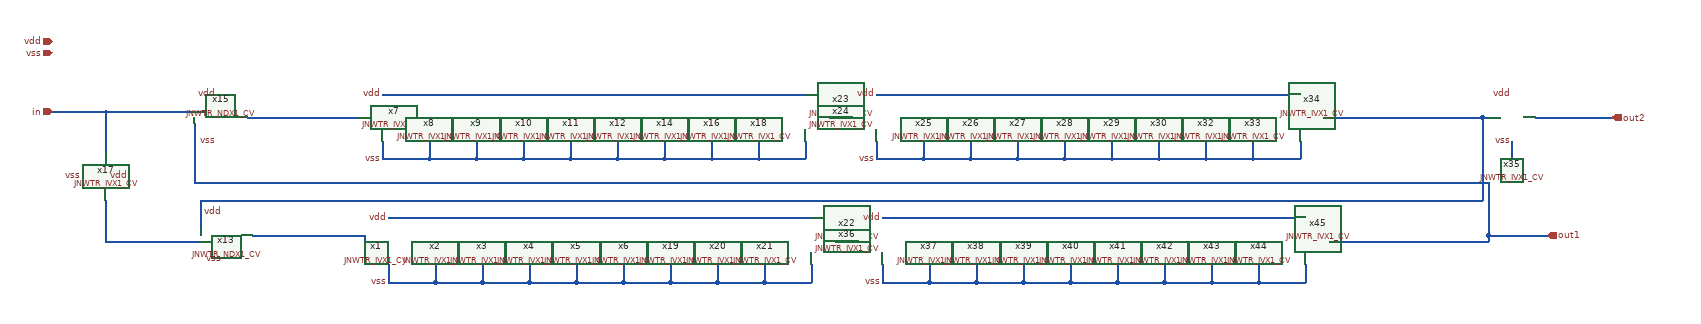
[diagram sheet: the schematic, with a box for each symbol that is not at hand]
v {xschem version=3.4.5 file_version=1.2
}
G {}
K {}
V {}
S {}
E {}
N 170 -220 170 -150 {
lab=#net1}
N 170 -150 330 -150 {
lab=#net1}
N 170 -370 320 -370 {
lab=in}
N 170 -370 170 -300 {
lab=in}
N 80 -370 170 -370 {
lab=in}
N 320 -250 2520 -250 {
lab=out1}
N 320 -350 320 -250 {
lab=out1}
N 330 -220 330 -170 {
lab=#net2}
N 2560 -320 2560 -290 {
lab=vss}
N 2520 -250 2520 -160 {
lab=out1}
N 640 -320 640 -290 {
lab=vss}
N 720 -320 720 -290 {
lab=vss}
N 800 -320 800 -290 {
lab=vss}
N 880 -320 880 -290 {
lab=vss}
N 960 -320 960 -290 {
lab=vss}
N 1040 -320 1040 -290 {
lab=vss}
N 960 -290 1040 -290 {
lab=vss}
N 640 -290 720 -290 {
lab=vss}
N 720 -290 800 -290 {
lab=vss}
N 800 -290 880 -290 {
lab=vss}
N 880 -290 960 -290 {
lab=vss}
N 2510 -360 2510 -220 {
lab=#net2}
N 2520 -160 2620 -160 {
lab=out1}
N 2600 -360 2730 -360 {
lab=out2}
N 1120 -320 1120 -290 {
lab=vss}
N 1200 -320 1200 -290 {
lab=vss}
N 1200 -290 1280 -290 {
lab=vss}
N 1040 -290 1120 -290 {
lab=vss}
N 1120 -290 1200 -290 {
lab=vss}
N 640 -400 1360 -400 {
lab=vdd}
N 1280 -290 1360 -290 {
lab=vss}
N 1280 -320 1280 -290 {
lab=vss}
N 1360 -320 1360 -290 {
lab=vss}
N 2510 -360 2520 -360 {
lab=#net2}
N 330 -220 2510 -220 {
lab=#net2}
N 650 -110 650 -80 {
lab=vss}
N 730 -110 730 -80 {
lab=vss}
N 810 -110 810 -80 {
lab=vss}
N 890 -110 890 -80 {
lab=vss}
N 970 -110 970 -80 {
lab=vss}
N 1050 -110 1050 -80 {
lab=vss}
N 970 -80 1050 -80 {
lab=vss}
N 650 -80 730 -80 {
lab=vss}
N 730 -80 810 -80 {
lab=vss}
N 810 -80 890 -80 {
lab=vss}
N 890 -80 970 -80 {
lab=vss}
N 1130 -110 1130 -80 {
lab=vss}
N 1210 -110 1210 -80 {
lab=vss}
N 1210 -80 1290 -80 {
lab=vss}
N 1050 -80 1130 -80 {
lab=vss}
N 1130 -80 1210 -80 {
lab=vss}
N 650 -190 1370 -190 {
lab=vdd}
N 1290 -80 1370 -80 {
lab=vss}
N 1290 -110 1290 -80 {
lab=vss}
N 1370 -110 1370 -80 {
lab=vss}
N 1480 -320 1480 -290 {
lab=vss}
N 1560 -320 1560 -290 {
lab=vss}
N 1640 -320 1640 -290 {
lab=vss}
N 1720 -320 1720 -290 {
lab=vss}
N 1800 -320 1800 -290 {
lab=vss}
N 1880 -320 1880 -290 {
lab=vss}
N 1800 -290 1880 -290 {
lab=vss}
N 1480 -290 1560 -290 {
lab=vss}
N 1560 -290 1640 -290 {
lab=vss}
N 1640 -290 1720 -290 {
lab=vss}
N 1720 -290 1800 -290 {
lab=vss}
N 1960 -320 1960 -290 {
lab=vss}
N 2040 -320 2040 -290 {
lab=vss}
N 2040 -290 2120 -290 {
lab=vss}
N 1880 -290 1960 -290 {
lab=vss}
N 1960 -290 2040 -290 {
lab=vss}
N 1480 -400 2200 -400 {
lab=vdd}
N 2120 -290 2200 -290 {
lab=vss}
N 2120 -320 2120 -290 {
lab=vss}
N 2200 -320 2200 -290 {
lab=vss}
N 1490 -110 1490 -80 {
lab=vss}
N 1570 -110 1570 -80 {
lab=vss}
N 1650 -110 1650 -80 {
lab=vss}
N 1730 -110 1730 -80 {
lab=vss}
N 1810 -110 1810 -80 {
lab=vss}
N 1890 -110 1890 -80 {
lab=vss}
N 1810 -80 1890 -80 {
lab=vss}
N 1490 -80 1570 -80 {
lab=vss}
N 1570 -80 1650 -80 {
lab=vss}
N 1650 -80 1730 -80 {
lab=vss}
N 1730 -80 1810 -80 {
lab=vss}
N 1970 -110 1970 -80 {
lab=vss}
N 2050 -110 2050 -80 {
lab=vss}
N 2050 -80 2130 -80 {
lab=vss}
N 1890 -80 1970 -80 {
lab=vss}
N 1970 -80 2050 -80 {
lab=vss}
N 1490 -190 2210 -190 {
lab=vdd}
N 2130 -80 2210 -80 {
lab=vss}
N 2130 -110 2130 -80 {
lab=vss}
N 2210 -110 2210 -80 {
lab=vss}
N 1410 -150 1450 -150 {
lab=#net3}
N 1400 -360 1440 -360 {
lab=#net4}
N 420 -160 610 -160 {
lab=#net5}
N 610 -160 610 -150 {
lab=#net5}
N 410 -360 600 -360 {
lab=#net6}
N 2240 -360 2510 -360 {
lab=#net2}
N 2250 -150 2520 -150 {
lab=out1}
N 2520 -160 2520 -150 {
lab=out1}
C {JNW_TR_SKY130A/JNWTR_NDX1_CV.sym} 330 -150 0 0 {name=x13 }
C {devices/lab_wire.sym} 370 -200 0 0 {name=p26 sig_type=std_logic lab=vdd}
C {devices/lab_wire.sym} 370 -120 0 0 {name=p27 sig_type=std_logic lab=vss
}
C {JNW_TR_SKY130A/JNWTR_NDX1_CV.sym} 320 -350 0 0 {name=x15 }
C {devices/lab_wire.sym} 360 -400 0 0 {name=p28 sig_type=std_logic lab=vdd}
C {devices/lab_wire.sym} 360 -320 0 0 {name=p30 sig_type=std_logic lab=vss
}
C {JNW_TR_SKY130A/JNWTR_IVX1_CV.sym} 170 -300 1 0 {name=x17 }
C {devices/lab_wire.sym} 130 -260 0 0 {name=p31 sig_type=std_logic lab=vss
}
C {devices/lab_wire.sym} 210 -260 0 0 {name=p33 sig_type=std_logic lab=vdd}
C {devices/ipin.sym} 80 -370 0 0 {name=p35 lab=in}
C {JNW_TR_SKY130A/JNWTR_IVX1_CV.sym} 2520 -360 0 0 {name=x35 }
C {devices/lab_wire.sym} 2560 -320 3 0 {name=p51 sig_type=std_logic lab=vss
}
C {devices/lab_wire.sym} 2560 -400 3 0 {name=p52 sig_type=std_logic lab=vdd}
C {devices/opin.sym} 2620 -160 0 0 {name=p1 lab=out1}
C {devices/opin.sym} 2730 -360 0 0 {name=p2 lab=out2}
C {devices/ipin.sym} 80 -470 0 0 {name=p3 lab=vss}
C {devices/ipin.sym} 80 -490 0 0 {name=p4 lab=vdd}
C {JNW_TR_SKY130A/JNWTR_IVX1_CV.sym} 600 -360 0 0 {name=x7 }
C {devices/lab_wire.sym} 640 -290 0 0 {name=p7 sig_type=std_logic lab=vss
}
C {devices/lab_wire.sym} 640 -400 0 0 {name=p8 sig_type=std_logic lab=vdd}
C {JNW_TR_SKY130A/JNWTR_IVX1_CV.sym} 680 -360 0 0 {name=x8 }
C {JNW_TR_SKY130A/JNWTR_IVX1_CV.sym} 760 -360 0 0 {name=x9 }
C {JNW_TR_SKY130A/JNWTR_IVX1_CV.sym} 840 -360 0 0 {name=x10 }
C {JNW_TR_SKY130A/JNWTR_IVX1_CV.sym} 920 -360 0 0 {name=x11 }
C {JNW_TR_SKY130A/JNWTR_IVX1_CV.sym} 1000 -360 0 0 {name=x12 }
C {JNW_TR_SKY130A/JNWTR_IVX1_CV.sym} 1080 -360 0 0 {name=x14 }
C {JNW_TR_SKY130A/JNWTR_IVX1_CV.sym} 1160 -360 0 0 {name=x16 }
C {JNW_TR_SKY130A/JNWTR_IVX1_CV.sym} 1240 -360 0 0 {name=x18 }
C {JNW_TR_SKY130A/JNWTR_IVX1_CV.sym} 1320 -360 0 0 {name=x23 }
C {JNW_TR_SKY130A/JNWTR_IVX1_CV.sym} 610 -150 0 0 {name=x1 }
C {devices/lab_wire.sym} 650 -80 0 0 {name=p5 sig_type=std_logic lab=vss
}
C {devices/lab_wire.sym} 650 -190 0 0 {name=p6 sig_type=std_logic lab=vdd}
C {JNW_TR_SKY130A/JNWTR_IVX1_CV.sym} 690 -150 0 0 {name=x2 }
C {JNW_TR_SKY130A/JNWTR_IVX1_CV.sym} 770 -150 0 0 {name=x3 }
C {JNW_TR_SKY130A/JNWTR_IVX1_CV.sym} 850 -150 0 0 {name=x4 }
C {JNW_TR_SKY130A/JNWTR_IVX1_CV.sym} 930 -150 0 0 {name=x5 }
C {JNW_TR_SKY130A/JNWTR_IVX1_CV.sym} 1010 -150 0 0 {name=x6 }
C {JNW_TR_SKY130A/JNWTR_IVX1_CV.sym} 1090 -150 0 0 {name=x19 }
C {JNW_TR_SKY130A/JNWTR_IVX1_CV.sym} 1170 -150 0 0 {name=x20 }
C {JNW_TR_SKY130A/JNWTR_IVX1_CV.sym} 1250 -150 0 0 {name=x21 }
C {JNW_TR_SKY130A/JNWTR_IVX1_CV.sym} 1330 -150 0 0 {name=x22 }
C {JNW_TR_SKY130A/JNWTR_IVX1_CV.sym} 1440 -360 0 0 {name=x24 }
C {devices/lab_wire.sym} 1480 -290 0 0 {name=p9 sig_type=std_logic lab=vss
}
C {devices/lab_wire.sym} 1480 -400 0 0 {name=p10 sig_type=std_logic lab=vdd}
C {JNW_TR_SKY130A/JNWTR_IVX1_CV.sym} 1520 -360 0 0 {name=x25 }
C {JNW_TR_SKY130A/JNWTR_IVX1_CV.sym} 1600 -360 0 0 {name=x26 }
C {JNW_TR_SKY130A/JNWTR_IVX1_CV.sym} 1680 -360 0 0 {name=x27 }
C {JNW_TR_SKY130A/JNWTR_IVX1_CV.sym} 1760 -360 0 0 {name=x28 }
C {JNW_TR_SKY130A/JNWTR_IVX1_CV.sym} 1840 -360 0 0 {name=x29 }
C {JNW_TR_SKY130A/JNWTR_IVX1_CV.sym} 1920 -360 0 0 {name=x30 }
C {JNW_TR_SKY130A/JNWTR_IVX1_CV.sym} 2000 -360 0 0 {name=x32 }
C {JNW_TR_SKY130A/JNWTR_IVX1_CV.sym} 2080 -360 0 0 {name=x33 }
C {JNW_TR_SKY130A/JNWTR_IVX1_CV.sym} 2160 -360 0 0 {name=x34 }
C {JNW_TR_SKY130A/JNWTR_IVX1_CV.sym} 1450 -150 0 0 {name=x36 }
C {devices/lab_wire.sym} 1490 -80 0 0 {name=p11 sig_type=std_logic lab=vss
}
C {devices/lab_wire.sym} 1490 -190 0 0 {name=p12 sig_type=std_logic lab=vdd}
C {JNW_TR_SKY130A/JNWTR_IVX1_CV.sym} 1530 -150 0 0 {name=x37 }
C {JNW_TR_SKY130A/JNWTR_IVX1_CV.sym} 1610 -150 0 0 {name=x38 }
C {JNW_TR_SKY130A/JNWTR_IVX1_CV.sym} 1690 -150 0 0 {name=x39 }
C {JNW_TR_SKY130A/JNWTR_IVX1_CV.sym} 1770 -150 0 0 {name=x40 }
C {JNW_TR_SKY130A/JNWTR_IVX1_CV.sym} 1850 -150 0 0 {name=x41 }
C {JNW_TR_SKY130A/JNWTR_IVX1_CV.sym} 1930 -150 0 0 {name=x42 }
C {JNW_TR_SKY130A/JNWTR_IVX1_CV.sym} 2010 -150 0 0 {name=x43 }
C {JNW_TR_SKY130A/JNWTR_IVX1_CV.sym} 2090 -150 0 0 {name=x44 }
C {JNW_TR_SKY130A/JNWTR_IVX1_CV.sym} 2170 -150 0 0 {name=x45 }
